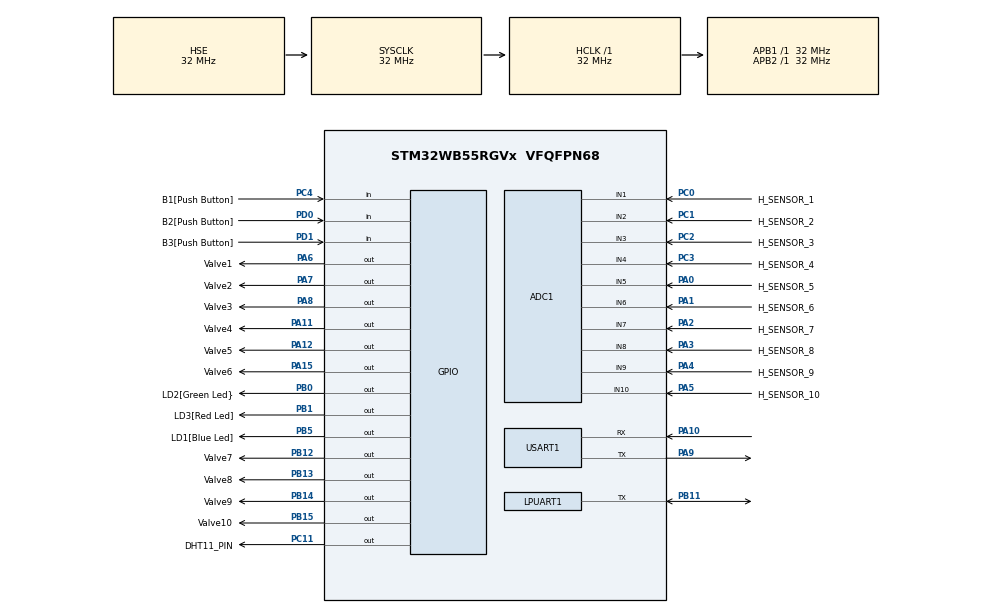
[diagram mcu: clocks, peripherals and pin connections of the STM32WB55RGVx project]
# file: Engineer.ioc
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ADC1.Channel-0\#ChannelRegularConversion=ADC_CHANNEL_2
ADC1.NbrOfConversionFlag=1
ADC1.OffsetNumber-0\#ChannelRegularConversion=ADC_OFFSET_NONE
ADC1.Rank-0\#ChannelRegularConversion=1
ADC1.SamplingTime-0\#ChannelRegularConversion=ADC_SAMPLETIME_2CYCLES_5
ADC1.master=1
Mcu.Family=STM32WB
Mcu.Name=STM32WB55RGVx
Mcu.Package=VFQFPN68
NVIC.PriorityGroup=NVIC_PRIORITYGROUP_4
OSC_IN.Mode=HSE-External-Oscillator
OSC_IN.Signal=RCC_OSC_IN
OSC_OUT.Mode=HSE-External-Oscillator
OSC_OUT.Signal=RCC_OSC_OUT
PA0.GPIO_Label=H_SENSOR_5
PA0.Signal=ADCx_IN5
PA1.GPIO_Label=H_SENSOR_6
PA1.Signal=ADCx_IN6
PA10.Mode=Asynchronous
PA10.Signal=USART1_RX
PA11.GPIO_Label=Valve4
PA11.Signal=GPIO_Output
PA12.GPIO_Label=Valve5
PA12.Signal=GPIO_Output
PA13.Mode=Trace_Asynchronous_SW
PA13.Signal=SYS_JTMS-SWDIO
PA14.Mode=Trace_Asynchronous_SW
PA14.Signal=SYS_JTCK-SWCLK
PA15.GPIO_Label=Valve6
PA15.Signal=GPIO_Output
PA2.GPIO_Label=H_SENSOR_7
PA2.Signal=ADCx_IN7
PA3.GPIO_Label=H_SENSOR_8
PA3.Signal=ADCx_IN8
PA4.GPIO_Label=H_SENSOR_9
PA4.Signal=ADCx_IN9
PA5.GPIO_Label=H_SENSOR_10
PA5.Signal=ADCx_IN10
PA6.GPIO_Label=Valve1
PA6.Signal=GPIO_Output
PA7.GPIO_Label=Valve2
PA7.Signal=GPIO_Output
PA8.GPIO_Label=Valve3
PA8.Signal=GPIO_Output
PA9.Mode=Asynchronous
PA9.Signal=USART1_TX
PB0.GPIO_Label=LD2[Green Led}
PB0.Signal=GPIO_Output
PB1.GPIO_Label=LD3[Red Led]
PB1.Signal=GPIO_Output
PB11.Mode=Half_duplex(single_wire_mode)
PB11.Signal=LPUART1_TX
PB12.GPIO_Label=Valve7
PB12.Signal=GPIO_Output
PB13.GPIO_Label=Valve8
PB13.Signal=GPIO_Output
PB14.GPIO_Label=Valve9
PB14.Signal=GPIO_Output
PB15.GPIO_Label=Valve10
PB15.Signal=GPIO_Output
PB3.Mode=Trace_Asynchronous_SW
PB3.Signal=SYS_JTDO-SWO
PB5.GPIO_Label=LD1[Blue Led]
PB5.Signal=GPIO_Output
PC0.GPIO_Label=H_SENSOR_1
PC0.Signal=ADCx_IN1
PC1.GPIO_Label=H_SENSOR_2
PC1.Signal=ADCx_IN2
PC11.GPIO_Label=DHT11_PIN
PC11.Signal=GPIO_Output
PC14-OSC32_IN.Mode=LSE-External-Oscillator
PC14-OSC32_IN.Signal=RCC_OSC32_IN
PC15-OSC32_OUT.Mode=LSE-External-Oscillator
PC15-OSC32_OUT.Signal=RCC_OSC32_OUT
PC2.GPIO_Label=H_SENSOR_3
PC2.Signal=ADCx_IN3
PC3.GPIO_Label=H_SENSOR_4
PC3.Signal=ADCx_IN4
PC4.GPIO_Label=B1[Push Button]
PC4.Signal=GPIO_Input
PD0.GPIO_Label=B2[Push Button]
PD0.Signal=GPIO_Input
PD1.GPIO_Label=B3[Push Button]
PD1.Signal=GPIO_Input
ProjectManager.HeapSize=0x200
ProjectManager.StackSize=0x400
ProjectManager.TargetToolchain=STM32CubeIDE
RCC.ADCFreq_Value=48000000
RCC.AHBFreq_Value=32000000
RCC.APB1Freq_Value=32000000
RCC.APB1TimFreq_Value=32000000
RCC.APB2Freq_Value=32000000
RCC.APB2TimFreq_Value=32000000
RCC.APB3Freq_Value=16000000
RCC.CortexFreq_Value=32000000
RCC.HCLKFreq_Value=32000000
RCC.HSE_VALUE=32000000
RCC.HSI48_VALUE=48000000
RCC.HSI_VALUE=16000000
RCC.MSIClockRange=RCC_MSIRANGE_10
RCC.PLLM=RCC_PLLM_DIV2
RCC.PLLSAI1N=6
RCC.SYSCLKFreq_VALUE=32000000
RCC.USBFreq_Value=48000000
RCC.VCOOutputFreq_Value=128000000
RF1.Mode=RF1_Activate
RF1.Signal=RF_RF1
SH.ADCx_IN1.0=ADC1_IN1,IN1-Single-Ended
SH.ADCx_IN10.0=ADC1_IN10,IN10-Single-Ended
SH.ADCx_IN2.0=ADC1_IN2,IN2-Single-Ended
SH.ADCx_IN3.0=ADC1_IN3,IN3-Single-Ended
SH.ADCx_IN4.0=ADC1_IN4,IN4-Single-Ended
SH.ADCx_IN5.0=ADC1_IN5,IN5-Single-Ended
SH.ADCx_IN6.0=ADC1_IN6,IN6-Single-Ended
SH.ADCx_IN7.0=ADC1_IN7,IN7-Single-Ended
SH.ADCx_IN8.0=ADC1_IN8,IN8-Single-Ended
SH.ADCx_IN9.0=ADC1_IN9,IN9-Single-Ended
STM32_WPAN.CFG_FAST_CONN_ADV_INTERVAL_MAX_HEXA=0xa0
STM32_WPAN.CFG_LP_CONN_ADV_INTERVAL_MAX_HEXA=0xfa0
STM32_WPAN.CUSTOM_TEMPLATE=Enabled
TIM1.Channel-Output\ Compare3\ No\ Output=TIM_CHANNEL_3
TIM2.Channel-Output\ Compare3\ No\ Output=TIM_CHANNEL_3
USART1.VirtualMode-Asynchronous=VM_ASYNC
VP_HSEM_VS_HSEM.Mode=HSEM_Activate
VP_RTC_VS_RTC_Activate.Mode=RTC_Enabled
VP_SEQUENCER_VS_SEQUENCER.Mode=SEQUENCER_Enabled
VP_STM32_WPAN_VS_BLE_HOST.Mode=STM32_WPAN_Enabled
VP_TIM1_VS_no_output3.Mode=Output Compare3 No Output
VP_TIM2_VS_no_output3.Mode=Output Compare3 No Output
VP_TINY_LPM_VS_TINY_LPM.Mode=TINY_LPM_Enabled
board=custom

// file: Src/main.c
/* USER CODE BEGIN Header */
/**
  ******************************************************************************
  * @file           : main.c
  * @brief          : Main program body
  ******************************************************************************
  * @attention
  *
  * <h2><center>&copy; Copyright (c) 2019 STMicroelectronics.
  * All rights reserved.</center></h2>
  *
  * This software component is licensed by ST under Ultimate Liberty license
  * SLA0044, the "License"; You may not use this file except in compliance with
  * the License. You may obtain a copy of the License at:
  *                             www.st.com/SLA0044
  *
  ******************************************************************************
  */
/* USER CODE END Header */

#include "main.h"
#include "app_entry.h"
#include "app_common.h"
#include "stm32_seq.h"

/* USER CODE BEGIN Includes */

#include "../WateringSystem/Inc/HumiditySensor.h"
#include "../WateringSystem/Inc/Valve.h"

/* USER CODE END Includes */

ADC_HandleTypeDef hadc1;
DMA_HandleTypeDef hdma_adc1;

UART_HandleTypeDef hlpuart1;
UART_HandleTypeDef huart1;

RTC_HandleTypeDef hrtc;

TIM_HandleTypeDef htim1;
TIM_HandleTypeDef htim2;

/* USER CODE BEGIN PV */

//uint16_t data[10];
//float test;
extern Watering_Set_t watering_set;

/* USER CODE END PV */

void SystemClock_Config(void);
static void MX_GPIO_Init(void);
static void MX_DMA_Init(void);
static void MX_ADC1_Init(void);
static void MX_LPUART1_UART_Init(void);
static void MX_USART1_UART_Init(void);
static void MX_RF_Init(void);
static void MX_RTC_Init(void);
static void MX_TIM1_Init(void);
static void MX_TIM2_Init(void);

int main(void)
{

  /* MCU Configuration--------------------------------------------------------*/

  /* Reset of all peripherals, Initializes the Flash interface and the Systick. */
  HAL_Init();

  /* Configure the system clock */
  SystemClock_Config();

  /* Initialize all configured peripherals */
  MX_GPIO_Init();
  MX_DMA_Init();
  MX_ADC1_Init();
  MX_LPUART1_UART_Init();
  MX_USART1_UART_Init();
  MX_RF_Init();
  MX_RTC_Init();
  MX_TIM1_Init();
  MX_TIM2_Init();
  /* USER CODE BEGIN 2 */
  SensorsInit(1);
  InitValves();
  /* USER CODE END 2 */

  /* Init code for STM32_WPAN */
  APPE_Init();
  /* Infinite loop */
  while (1)
  {
	  UTIL_SEQ_Run(UTIL_SEQ_DEFAULT);
  }
}

void SystemClock_Config(void)
{
  RCC_OscInitTypeDef RCC_OscInitStruct = {0};
  RCC_ClkInitTypeDef RCC_ClkInitStruct = {0};
  RCC_PeriphCLKInitTypeDef PeriphClkInitStruct = {0};

  /** Macro to configure the PLL multiplication factor
  */
  __HAL_RCC_PLL_PLLM_CONFIG(RCC_PLLM_DIV2);
  /** Macro to configure the PLL clock source
  */
  __HAL_RCC_PLL_PLLSOURCE_CONFIG(RCC_PLLSOURCE_MSI);
  /** Configure LSE Drive Capability
  */
  __HAL_RCC_LSEDRIVE_CONFIG(RCC_LSEDRIVE_LOW);
  /** Configure the main internal regulator output voltage
  */
  __HAL_PWR_VOLTAGESCALING_CONFIG(PWR_REGULATOR_VOLTAGE_SCALE1);
  /** Initializes the CPU, AHB and APB busses clocks
  */
  RCC_OscInitStruct.OscillatorType = RCC_OSCILLATORTYPE_HSI|RCC_OSCILLATORTYPE_HSE
                              |RCC_OSCILLATORTYPE_LSE|RCC_OSCILLATORTYPE_MSI;
  RCC_OscInitStruct.HSEState = RCC_HSE_ON;
  RCC_OscInitStruct.LSEState = RCC_LSE_ON;
  RCC_OscInitStruct.HSIState = RCC_HSI_ON;
  RCC_OscInitStruct.MSIState = RCC_MSI_ON;
  RCC_OscInitStruct.HSICalibrationValue = RCC_HSICALIBRATION_DEFAULT;
  RCC_OscInitStruct.MSICalibrationValue = RCC_MSICALIBRATION_DEFAULT;
  RCC_OscInitStruct.MSIClockRange = RCC_MSIRANGE_10;
  RCC_OscInitStruct.PLL.PLLState = RCC_PLL_NONE;
  if (HAL_RCC_OscConfig(&RCC_OscInitStruct) != HAL_OK)
  {
    Error_Handler();
  }
  /** Configure the SYSCLKSource, HCLK, PCLK1 and PCLK2 clocks dividers
  */
  RCC_ClkInitStruct.ClockType = RCC_CLOCKTYPE_HCLK4|RCC_CLOCKTYPE_HCLK2
                              |RCC_CLOCKTYPE_HCLK|RCC_CLOCKTYPE_SYSCLK
                              |RCC_CLOCKTYPE_PCLK1|RCC_CLOCKTYPE_PCLK2;
  RCC_ClkInitStruct.SYSCLKSource = RCC_SYSCLKSOURCE_HSE;
  RCC_ClkInitStruct.AHBCLKDivider = RCC_SYSCLK_DIV1;
  RCC_ClkInitStruct.APB1CLKDivider = RCC_HCLK_DIV1;
  RCC_ClkInitStruct.APB2CLKDivider = RCC_HCLK_DIV1;
  RCC_ClkInitStruct.AHBCLK2Divider = RCC_SYSCLK_DIV1;
  RCC_ClkInitStruct.AHBCLK4Divider = RCC_SYSCLK_DIV1;

  if (HAL_RCC_ClockConfig(&RCC_ClkInitStruct, FLASH_LATENCY_1) != HAL_OK)
  {
    Error_Handler();
  }
  /** Initializes the peripherals clocks
  */
  PeriphClkInitStruct.PeriphClockSelection = RCC_PERIPHCLK_SMPS|RCC_PERIPHCLK_RFWAKEUP
                              |RCC_PERIPHCLK_RTC|RCC_PERIPHCLK_USART1
                              |RCC_PERIPHCLK_LPUART1|RCC_PERIPHCLK_ADC;
  PeriphClkInitStruct.PLLSAI1.PLLN = 6;
  PeriphClkInitStruct.PLLSAI1.PLLP = RCC_PLLP_DIV2;
  PeriphClkInitStruct.PLLSAI1.PLLQ = RCC_PLLQ_DIV2;
  PeriphClkInitStruct.PLLSAI1.PLLR = RCC_PLLR_DIV2;
  PeriphClkInitStruct.PLLSAI1.PLLSAI1ClockOut = RCC_PLLSAI1_ADCCLK;
  PeriphClkInitStruct.Usart1ClockSelection = RCC_USART1CLKSOURCE_PCLK2;
  PeriphClkInitStruct.Lpuart1ClockSelection = RCC_LPUART1CLKSOURCE_PCLK1;
  PeriphClkInitStruct.AdcClockSelection = RCC_ADCCLKSOURCE_PLLSAI1;
  PeriphClkInitStruct.RTCClockSelection = RCC_RTCCLKSOURCE_LSE;
  PeriphClkInitStruct.RFWakeUpClockSelection = RCC_RFWKPCLKSOURCE_LSE;
  PeriphClkInitStruct.SmpsClockSelection = RCC_SMPSCLKSOURCE_HSE;
  PeriphClkInitStruct.SmpsDivSelection = RCC_SMPSCLKDIV_RANGE0;

  if (HAL_RCCEx_PeriphCLKConfig(&PeriphClkInitStruct) != HAL_OK)
  {
    Error_Handler();
  }
}

static void MX_ADC1_Init(void)
{

  ADC_ChannelConfTypeDef sConfig = {0};

  /** Common config
  */
  hadc1.Instance = ADC1;
//  hadc1.Init.ClockPrescaler = ADC_CLOCK_ASYNC_DIV2;
  hadc1.Init.ClockPrescaler = ADC_CLOCK_ASYNC_DIV12;
  hadc1.Init.Resolution = ADC_RESOLUTION_12B;
  hadc1.Init.DataAlign = ADC_DATAALIGN_RIGHT;
  hadc1.Init.ScanConvMode = ADC_SCAN_ENABLE;
  hadc1.Init.EOCSelection = ADC_EOC_SINGLE_CONV;
  hadc1.Init.LowPowerAutoWait = DISABLE;
  hadc1.Init.ContinuousConvMode = ENABLE;
  hadc1.Init.NbrOfConversion = 10;
  hadc1.Init.DiscontinuousConvMode = DISABLE;
  hadc1.Init.ExternalTrigConv = ADC_SOFTWARE_START;
  hadc1.Init.ExternalTrigConvEdge = ADC_EXTERNALTRIGCONVEDGE_NONE;
  hadc1.Init.DMAContinuousRequests = ENABLE;
  hadc1.Init.Overrun = ADC_OVR_DATA_PRESERVED;
  hadc1.Init.OversamplingMode = DISABLE;
  if (HAL_ADC_Init(&hadc1) != HAL_OK)
  {
    Error_Handler();
  }
  /** Configure Regular Channel
  */
  sConfig.Channel = ADC_CHANNEL_1;
  sConfig.Rank = ADC_REGULAR_RANK_1;
  sConfig.SamplingTime = ADC_SAMPLETIME_2CYCLES_5;
  sConfig.SingleDiff = ADC_SINGLE_ENDED;
  sConfig.OffsetNumber = ADC_OFFSET_NONE;
  sConfig.Offset = 0;
  if (HAL_ADC_ConfigChannel(&hadc1, &sConfig) != HAL_OK)
  {
    Error_Handler();
  }
  /** Configure Regular Channel
  */
  sConfig.Channel = ADC_CHANNEL_2;
  sConfig.Rank = ADC_REGULAR_RANK_2;
  if (HAL_ADC_ConfigChannel(&hadc1, &sConfig) != HAL_OK)
  {
    Error_Handler();
  }
  /** Configure Regular Channel
  */
  sConfig.Channel = ADC_CHANNEL_3;
  sConfig.Rank = ADC_REGULAR_RANK_3;
  if (HAL_ADC_ConfigChannel(&hadc1, &sConfig) != HAL_OK)
  {
    Error_Handler();
  }
  /** Configure Regular Channel
  */
  sConfig.Channel = ADC_CHANNEL_4;
  sConfig.Rank = ADC_REGULAR_RANK_4;
  if (HAL_ADC_ConfigChannel(&hadc1, &sConfig) != HAL_OK)
  {
    Error_Handler();
  }
  /** Configure Regular Channel
  */
  sConfig.Channel = ADC_CHANNEL_5;
  sConfig.Rank = ADC_REGULAR_RANK_5;
  if (HAL_ADC_ConfigChannel(&hadc1, &sConfig) != HAL_OK)
  {
    Error_Handler();
  }
  /** Configure Regular Channel
  */
  sConfig.Channel = ADC_CHANNEL_6;
  sConfig.Rank = ADC_REGULAR_RANK_6;
  if (HAL_ADC_ConfigChannel(&hadc1, &sConfig) != HAL_OK)
  {
    Error_Handler();
  }
  /** Configure Regular Channel
  */
  sConfig.Channel = ADC_CHANNEL_7;
  sConfig.Rank = ADC_REGULAR_RANK_7;
  if (HAL_ADC_ConfigChannel(&hadc1, &sConfig) != HAL_OK)
  {
    Error_Handler();
  }
  /** Configure Regular Channel
  */
  sConfig.Channel = ADC_CHANNEL_8;
  sConfig.Rank = ADC_REGULAR_RANK_8;
  if (HAL_ADC_ConfigChannel(&hadc1, &sConfig) != HAL_OK)
  {
    Error_Handler();
  }
  /** Configure Regular Channel
  */
  sConfig.Channel = ADC_CHANNEL_9;
  sConfig.Rank = ADC_REGULAR_RANK_9;
  if (HAL_ADC_ConfigChannel(&hadc1, &sConfig) != HAL_OK)
  {
    Error_Handler();
  }
  /** Configure Regular Channel
  */
  sConfig.Channel = ADC_CHANNEL_10;
  sConfig.Rank = ADC_REGULAR_RANK_10;
  if (HAL_ADC_ConfigChannel(&hadc1, &sConfig) != HAL_OK)
  {
    Error_Handler();
  }
  /* USER CODE BEGIN ADC1_Init 2 */
  //TODO: Reconsider Config of ADC and DMA
  /* USER CODE END ADC1_Init 2 */

}

static void MX_LPUART1_UART_Init(void)
{

  hlpuart1.Instance = LPUART1;
  hlpuart1.Init.BaudRate = 209700;
  hlpuart1.Init.WordLength = UART_WORDLENGTH_7B;
  hlpuart1.Init.StopBits = UART_STOPBITS_1;
  hlpuart1.Init.Parity = UART_PARITY_NONE;
  hlpuart1.Init.Mode = UART_MODE_TX_RX;
  hlpuart1.Init.HwFlowCtl = UART_HWCONTROL_NONE;
  hlpuart1.Init.OneBitSampling = UART_ONE_BIT_SAMPLE_DISABLE;
  hlpuart1.Init.ClockPrescaler = UART_PRESCALER_DIV1;
  hlpuart1.AdvancedInit.AdvFeatureInit = UART_ADVFEATURE_NO_INIT;
  if (HAL_HalfDuplex_Init(&hlpuart1) != HAL_OK)
  {
    Error_Handler();
  }
  if (HAL_UARTEx_SetTxFifoThreshold(&hlpuart1, UART_TXFIFO_THRESHOLD_1_8) != HAL_OK)
  {
    Error_Handler();
  }
  if (HAL_UARTEx_SetRxFifoThreshold(&hlpuart1, UART_RXFIFO_THRESHOLD_1_8) != HAL_OK)
  {
    Error_Handler();
  }
  if (HAL_UARTEx_DisableFifoMode(&hlpuart1) != HAL_OK)
  {
    Error_Handler();
  }

}

static void MX_USART1_UART_Init(void)
{

  huart1.Instance = USART1;
  huart1.Init.BaudRate = 115200;
  huart1.Init.WordLength = UART_WORDLENGTH_7B;
  huart1.Init.StopBits = UART_STOPBITS_1;
  huart1.Init.Parity = UART_PARITY_NONE;
  huart1.Init.Mode = UART_MODE_TX_RX;
  huart1.Init.HwFlowCtl = UART_HWCONTROL_NONE;
  huart1.Init.OverSampling = UART_OVERSAMPLING_16;
  huart1.Init.OneBitSampling = UART_ONE_BIT_SAMPLE_DISABLE;
  huart1.Init.ClockPrescaler = UART_PRESCALER_DIV1;
  huart1.AdvancedInit.AdvFeatureInit = UART_ADVFEATURE_NO_INIT;
  if (HAL_UART_Init(&huart1) != HAL_OK)
  {
    Error_Handler();
  }
  if (HAL_UARTEx_SetTxFifoThreshold(&huart1, UART_TXFIFO_THRESHOLD_1_8) != HAL_OK)
  {
    Error_Handler();
  }
  if (HAL_UARTEx_SetRxFifoThreshold(&huart1, UART_RXFIFO_THRESHOLD_1_8) != HAL_OK)
  {
    Error_Handler();
  }
  if (HAL_UARTEx_DisableFifoMode(&huart1) != HAL_OK)
  {
    Error_Handler();
  }

}

static void MX_RF_Init(void)
{

}

static void MX_RTC_Init(void)
{

  /** Initialize RTC Only
  */
  hrtc.Instance = RTC;
  hrtc.Init.HourFormat = RTC_HOURFORMAT_24;
  hrtc.Init.AsynchPrediv = CFG_RTC_ASYNCH_PRESCALER;
  hrtc.Init.SynchPrediv = CFG_RTC_SYNCH_PRESCALER ;
  hrtc.Init.OutPut = RTC_OUTPUT_DISABLE;
  hrtc.Init.OutPutPolarity = RTC_OUTPUT_POLARITY_HIGH;
  hrtc.Init.OutPutType = RTC_OUTPUT_TYPE_OPENDRAIN;
  if (HAL_RTC_Init(&hrtc) != HAL_OK)
  {
    Error_Handler();
  }

}

static void MX_TIM1_Init(void)
{

  TIM_MasterConfigTypeDef sMasterConfig = {0};
  TIM_OC_InitTypeDef sConfigOC = {0};
  TIM_BreakDeadTimeConfigTypeDef sBreakDeadTimeConfig = {0};

  htim1.Instance = TIM1;
  htim1.Init.Prescaler = 0;
  htim1.Init.CounterMode = TIM_COUNTERMODE_UP;
  htim1.Init.Period = 0;
  htim1.Init.ClockDivision = TIM_CLOCKDIVISION_DIV1;
  htim1.Init.RepetitionCounter = 0;
  htim1.Init.AutoReloadPreload = TIM_AUTORELOAD_PRELOAD_DISABLE;
  if (HAL_TIM_OC_Init(&htim1) != HAL_OK)
  {
    Error_Handler();
  }
  sMasterConfig.MasterOutputTrigger = TIM_TRGO_RESET;
  sMasterConfig.MasterOutputTrigger2 = TIM_TRGO2_RESET;
  sMasterConfig.MasterSlaveMode = TIM_MASTERSLAVEMODE_DISABLE;
  if (HAL_TIMEx_MasterConfigSynchronization(&htim1, &sMasterConfig) != HAL_OK)
  {
    Error_Handler();
  }
  sConfigOC.OCMode = TIM_OCMODE_TIMING;
  sConfigOC.Pulse = 0;
  sConfigOC.OCPolarity = TIM_OCPOLARITY_HIGH;
  sConfigOC.OCNPolarity = TIM_OCNPOLARITY_HIGH;
  sConfigOC.OCFastMode = TIM_OCFAST_DISABLE;
  sConfigOC.OCIdleState = TIM_OCIDLESTATE_RESET;
  sConfigOC.OCNIdleState = TIM_OCNIDLESTATE_RESET;
  if (HAL_TIM_OC_ConfigChannel(&htim1, &sConfigOC, TIM_CHANNEL_3) != HAL_OK)
  {
    Error_Handler();
  }
  sBreakDeadTimeConfig.OffStateRunMode = TIM_OSSR_DISABLE;
  sBreakDeadTimeConfig.OffStateIDLEMode = TIM_OSSI_DISABLE;
  sBreakDeadTimeConfig.LockLevel = TIM_LOCKLEVEL_OFF;
  sBreakDeadTimeConfig.DeadTime = 0;
  sBreakDeadTimeConfig.BreakState = TIM_BREAK_DISABLE;
  sBreakDeadTimeConfig.BreakPolarity = TIM_BREAKPOLARITY_HIGH;
  sBreakDeadTimeConfig.BreakFilter = 0;
  sBreakDeadTimeConfig.Break2State = TIM_BREAK2_DISABLE;
  sBreakDeadTimeConfig.Break2Polarity = TIM_BREAK2POLARITY_HIGH;
  sBreakDeadTimeConfig.Break2Filter = 0;
  sBreakDeadTimeConfig.AutomaticOutput = TIM_AUTOMATICOUTPUT_DISABLE;
  if (HAL_TIMEx_ConfigBreakDeadTime(&htim1, &sBreakDeadTimeConfig) != HAL_OK)
  {
    Error_Handler();
  }

}

static void MX_TIM2_Init(void)
{

  TIM_MasterConfigTypeDef sMasterConfig = {0};
  TIM_OC_InitTypeDef sConfigOC = {0};

  htim2.Instance = TIM2;
  htim2.Init.Prescaler = 0;
  htim2.Init.CounterMode = TIM_COUNTERMODE_UP;
  htim2.Init.Period = 0;
  htim2.Init.ClockDivision = TIM_CLOCKDIVISION_DIV1;
  htim2.Init.AutoReloadPreload = TIM_AUTORELOAD_PRELOAD_DISABLE;
  if (HAL_TIM_OC_Init(&htim2) != HAL_OK)
  {
    Error_Handler();
  }
  sMasterConfig.MasterOutputTrigger = TIM_TRGO_RESET;
  sMasterConfig.MasterSlaveMode = TIM_MASTERSLAVEMODE_DISABLE;
  if (HAL_TIMEx_MasterConfigSynchronization(&htim2, &sMasterConfig) != HAL_OK)
  {
    Error_Handler();
  }
  sConfigOC.OCMode = TIM_OCMODE_TIMING;
  sConfigOC.Pulse = 0;
  sConfigOC.OCPolarity = TIM_OCPOLARITY_HIGH;
  sConfigOC.OCFastMode = TIM_OCFAST_DISABLE;
  if (HAL_TIM_OC_ConfigChannel(&htim2, &sConfigOC, TIM_CHANNEL_3) != HAL_OK)
  {
    Error_Handler();
  }

}

static void MX_DMA_Init(void)
{

  /* DMA controller clock enable */
  __HAL_RCC_DMAMUX1_CLK_ENABLE();
  __HAL_RCC_DMA1_CLK_ENABLE();

  /* DMA interrupt init */
  /* DMA1_Channel1_IRQn interrupt configuration */
  HAL_NVIC_SetPriority(DMA1_Channel1_IRQn, 0, 0);
  HAL_NVIC_EnableIRQ(DMA1_Channel1_IRQn);

}

static void MX_GPIO_Init(void)
{
  GPIO_InitTypeDef GPIO_InitStruct = {0};

  /* GPIO Ports Clock Enable */
  __HAL_RCC_GPIOC_CLK_ENABLE();
  __HAL_RCC_GPIOA_CLK_ENABLE();
  __HAL_RCC_GPIOB_CLK_ENABLE();
  __HAL_RCC_GPIOD_CLK_ENABLE();

  /*Configure GPIO pin Output Level */
  HAL_GPIO_WritePin(GPIOA, Valve1_Pin|Valve2_Pin|Valve3_Pin|Valve4_Pin
                          |Valve5_Pin|Valve6_Pin, GPIO_PIN_RESET);

  /*Configure GPIO pin Output Level */
  HAL_GPIO_WritePin(GPIOB, GREEN_LED_Pin|RED_LED_Pin|Valve7_Pin|Valve8_Pin
                          |Valve9_Pin|Valve10_Pin|BLUE_LED_Pin, GPIO_PIN_RESET);

  /*Configure GPIO pin Output Level */
  HAL_GPIO_WritePin(DHT11_PIN_GPIO_Port, DHT11_PIN_Pin, GPIO_PIN_RESET);

  /*Configure GPIO pins : Valve1_Pin Valve2_Pin Valve3_Pin Valve4_Pin
                           Valve5_Pin Valve6_Pin */
  GPIO_InitStruct.Pin = Valve1_Pin|Valve2_Pin|Valve3_Pin|Valve4_Pin
                          |Valve5_Pin|Valve6_Pin;
  GPIO_InitStruct.Mode = GPIO_MODE_OUTPUT_PP;
  GPIO_InitStruct.Pull = GPIO_NOPULL;
  GPIO_InitStruct.Speed = GPIO_SPEED_FREQ_LOW;
  HAL_GPIO_Init(GPIOA, &GPIO_InitStruct);

  /*Configure GPIO pin : B1_Pin */
  GPIO_InitStruct.Pin = B1_Pin;
  GPIO_InitStruct.Mode = GPIO_MODE_INPUT;
  GPIO_InitStruct.Pull = GPIO_NOPULL;
  HAL_GPIO_Init(B1_GPIO_Port, &GPIO_InitStruct);

  /*Configure GPIO pins : GREEN_LED_Pin RED_LED_Pin Valve7_Pin Valve8_Pin
                           Valve9_Pin Valve10_Pin BLUE_LED_Pin */
  GPIO_InitStruct.Pin = GREEN_LED_Pin|RED_LED_Pin|Valve7_Pin|Valve8_Pin
                          |Valve9_Pin|Valve10_Pin|BLUE_LED_Pin;
  GPIO_InitStruct.Mode = GPIO_MODE_OUTPUT_PP;
  GPIO_InitStruct.Pull = GPIO_NOPULL;
  GPIO_InitStruct.Speed = GPIO_SPEED_FREQ_LOW;
  HAL_GPIO_Init(GPIOB, &GPIO_InitStruct);

  /*Configure GPIO pin : DHT11_PIN_Pin */
  GPIO_InitStruct.Pin = DHT11_PIN_Pin;
  GPIO_InitStruct.Mode = GPIO_MODE_OUTPUT_PP;
  GPIO_InitStruct.Pull = GPIO_NOPULL;
  GPIO_InitStruct.Speed = GPIO_SPEED_FREQ_LOW;
  HAL_GPIO_Init(DHT11_PIN_GPIO_Port, &GPIO_InitStruct);

  /*Configure GPIO pins : B2_Pin B3_Pin */
  GPIO_InitStruct.Pin = B2_Pin|B3_Pin;
  GPIO_InitStruct.Mode = GPIO_MODE_INPUT;
  GPIO_InitStruct.Pull = GPIO_NOPULL;
  HAL_GPIO_Init(GPIOD, &GPIO_InitStruct);

}

/* USER CODE BEGIN 4 */

void HAL_ADC_ConvCpltCallback(ADC_HandleTypeDef *hadc)
{
	if(watering_set.flags && watering_set.working_stations)
	{
		watering_set.flags = 0;
		UTIL_SEQ_SetTask(1 << CFG_TASK_CONTROL_WATERING_SYSTEM, 1);
	}
}
/* USER CODE END 4 */

void Error_Handler(void)
{
}

/************************ (C) COPYRIGHT STMicroelectronics *****END OF FILE****/
